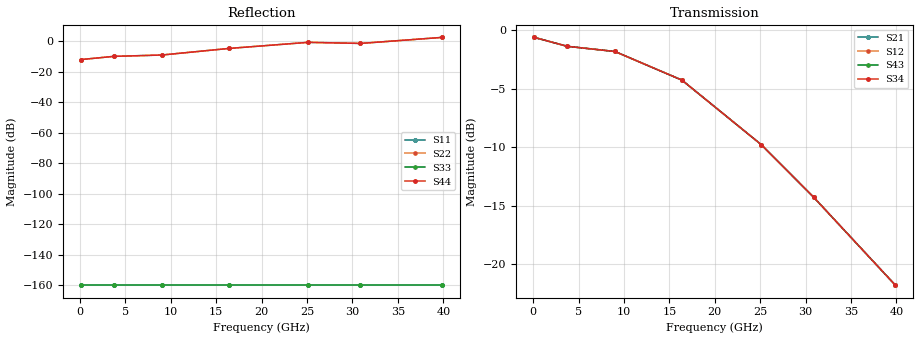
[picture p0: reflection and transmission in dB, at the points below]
! 26-Jun-2017 15:42:03
# Hz S RI R 50
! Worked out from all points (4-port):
!   319 points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, 125 MHz to 39.88 GHz, reference 50 ohm
!   strongest paths, dB at 125 MHz, 10 GHz, 20 GHz, 30 GHz, 39.88 GHz:
!     S43: -0.6, -1.9, -6.3, -13.6, -21.8
!     S21: -0.6, -1.9, -6.3, -13.6, -21.8
!     S42: -, -, -, -, -
!     S41: -, -, -, -, -
!     S32: -, -, -, -, -
!     S31: -, -, -, -, -
!   lowest |S11| = - dB at 125 MHz (marker M1), VSWR 1.00, Z = 50 + j0 ohm
!   |S11| at or under -10 dB: start of sweep to end of sweep
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1.25e8  0 0  0.9314 -0.0217  0 0  0 0
        0.9314 -0.0217  -0.2523 -0.00349  0 0  0 0
        0 0  0 0  0 0  0.9314 -0.0217
        0 0  0 0  0.9314 -0.0217  -0.2523 -0.00349
3.75e9  0 0  0.7012 -0.4864  0 0  0 0
        0.7012 -0.4864  -0.32 -0.0282  0 0  0 0
        0 0  0 0  0 0  0.7012 -0.4864
        0 0  0 0  0.7012 -0.4864  -0.32 -0.0282
9e9  0 0  0.1602 -0.795  0 0  0 0
     0.1602 -0.795  -0.3548 -0.0102  0 0  0 0
     0 0  0 0  0 0  0.1602 -0.795
     0 0  0 0  0.1602 -0.795  -0.3548 -0.0102
1.6375e10  0 0  -0.5199 -0.3234  0 0  0 0
           -0.5199 -0.3234  -0.5759 0.0922  0 0  0 0
           0 0  0 0  0 0  -0.5199 -0.3234
           0 0  0 0  -0.5199 -0.3234  -0.5759 0.0922
2.5125e10  0 0  -0.2436 0.2141  0 0  0 0
           -0.2436 0.2141  -0.8466 0.3758  0 0  0 0
           0 0  0 0  0 0  -0.2436 0.2141
           0 0  0 0  -0.2436 0.2141  -0.8466 0.3758
3.0875e10  0 0  -0.0192 0.1927  0 0  0 0
           -0.0192 0.1927  -0.7082 0.4754  0 0  0 0
           0 0  0 0  0 0  -0.0192 0.1927
           0 0  0 0  -0.0192 0.1927  -0.7082 0.4754
3.9875e10  0 0  0.0746 0.0328  0 0  0 0
           0.0746 0.0328  -1.155 0.6919  0 0  0 0
           0 0  0 0  0 0  0.0746 0.0328
           0 0  0 0  0.0746 0.0328  -1.155 0.6919
